VERSION 5.7 ;
BUSBITCHARS "[]" ;
DIVIDERCHAR "/" ;

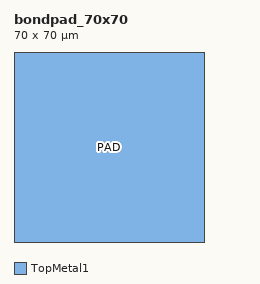
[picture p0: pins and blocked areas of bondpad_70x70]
MACRO bondpad_70x70
    CLASS COVER ;
    ORIGIN 0.000 0.000 ;
    FOREIGN bondpad_70x70 0.000 0.000 ;
    SIZE 70.000 BY 70.000 ;
    SYMMETRY X Y R90 ;
    SITE sg13cmos5l_ioSite ;
  PIN PAD
    DIRECTION INOUT ;
    USE SIGNAL ;
    PORT
      LAYER TopMetal1 ;
        RECT 0.000 0.000 70.000 70.000 ;
    END
  END PAD
  OBS
    LAYER Metal1 ;
      RECT 0.000 0.000 70.000 70.000 ;
    LAYER Metal2 ;
      RECT 0.000 0.000 70.000 70.000 ;
    LAYER Metal3 ;
      RECT 0.000 0.000 70.000 70.000 ;
    LAYER Metal4 ;
      RECT 0.000 0.000 70.000 70.000 ;
  END
END bondpad_70x70

END LIBRARY
